###############################################################
#  Generated by:      Cadence Innovus 21.16-s078_1
#  OS:                Linux x86_64(Host ID tc-01a0e839f97e)
#  Generated on:      Wed Nov  4 16:08:58 2026
#  Design:            my_soc_top
#  Command:           write_lef_abstract -5.8 -cutObsMinSpacing -specifyTopLayer METAL6 ../my_soc_top/outputs/manual_final/my_soc_top.lef
###############################################################

VERSION 5.8 ;

BUSBITCHARS "[]" ;
DIVIDERCHAR "/" ;

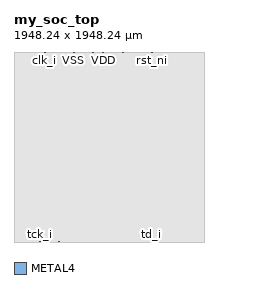
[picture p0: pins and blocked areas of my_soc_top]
MACRO my_soc_top
  CLASS BLOCK ;
  SIZE 1948.240000 BY 1948.240000 ;
  FOREIGN my_soc_top 0.000000 0.000000 ;
  ORIGIN 0 0 ;
  SYMMETRY X Y R90 ;
  PIN clk_i
    DIRECTION INPUT ;
    USE SIGNAL ;
    ANTENNADIFFAREA 1919.04 LAYER METAL4  ;
    ANTENNAPARTIALMETALAREA 298 LAYER METAL4  ;
    ANTENNAPARTIALMETALSIDEAREA 116.812 LAYER METAL4  ;
    ANTENNAMODEL OXIDE1 ;
    ANTENNAGATEAREA 7.5 LAYER METAL4  ;
    ANTENNAMAXAREACAR 92.4967 LAYER METAL4  ;
    ANTENNAMAXSIDEAREACAR 157.132 LAYER METAL4  ;
    ANTENNAMAXCUTCAR 15.6832 LAYER VIA45  ;
    PORT
      LAYER METAL4 ;
        RECT 310.000000 1945.840000 320.000000 1946.840000 ;
    END
  END clk_i
  PIN rst_ni
    DIRECTION INPUT ;
    USE SIGNAL ;
    ANTENNADIFFAREA 1919.04 LAYER METAL4  ;
    ANTENNAPARTIALMETALAREA 298 LAYER METAL4  ;
    ANTENNAPARTIALMETALSIDEAREA 116.812 LAYER METAL4  ;
    ANTENNAMODEL OXIDE1 ;
    ANTENNAGATEAREA 7.5 LAYER METAL4  ;
    ANTENNAMAXAREACAR 92.4967 LAYER METAL4  ;
    ANTENNAMAXSIDEAREACAR 157.132 LAYER METAL4  ;
    ANTENNAMAXCUTCAR 15.6832 LAYER VIA45  ;
    PORT
      LAYER METAL4 ;
        RECT 1410.000000 1945.840000 1420.000000 1946.840000 ;
    END
  END rst_ni
  PIN tck_i
    DIRECTION INPUT ;
    USE SIGNAL ;
    ANTENNADIFFAREA 1919.04 LAYER METAL4  ;
    ANTENNAPARTIALMETALAREA 298 LAYER METAL4  ;
    ANTENNAPARTIALMETALSIDEAREA 116.812 LAYER METAL4  ;
    ANTENNAMODEL OXIDE1 ;
    ANTENNAGATEAREA 7.5 LAYER METAL4  ;
    ANTENNAMAXAREACAR 92.4967 LAYER METAL4  ;
    ANTENNAMAXSIDEAREACAR 157.132 LAYER METAL4  ;
    ANTENNAMAXCUTCAR 15.6832 LAYER VIA45  ;
    PORT
      LAYER METAL4 ;
        RECT 260.000000 1.000000 270.000000 2.000000 ;
    END
  END tck_i
  PIN tms_i
    DIRECTION INPUT ;
    USE SIGNAL ;
    ANTENNADIFFAREA 1919.04 LAYER METAL4  ;
    ANTENNAPARTIALMETALAREA 298 LAYER METAL4  ;
    ANTENNAPARTIALMETALSIDEAREA 116.812 LAYER METAL4  ;
    ANTENNAMODEL OXIDE1 ;
    ANTENNAGATEAREA 7.5 LAYER METAL4  ;
    ANTENNAMAXAREACAR 92.4967 LAYER METAL4  ;
    ANTENNAMAXSIDEAREACAR 157.132 LAYER METAL4  ;
    ANTENNAMAXCUTCAR 15.6832 LAYER VIA45  ;
    PORT
      LAYER METAL4 ;
        RECT 460.000000 1.000000 470.000000 2.000000 ;
    END
  END tms_i
  PIN td_i
    DIRECTION INPUT ;
    USE SIGNAL ;
    ANTENNADIFFAREA 1919.04 LAYER METAL4  ;
    ANTENNAPARTIALMETALAREA 298 LAYER METAL4  ;
    ANTENNAPARTIALMETALSIDEAREA 116.812 LAYER METAL4  ;
    ANTENNAMODEL OXIDE1 ;
    ANTENNAGATEAREA 7.5 LAYER METAL4  ;
    ANTENNAMAXAREACAR 92.4967 LAYER METAL4  ;
    ANTENNAMAXSIDEAREACAR 157.132 LAYER METAL4  ;
    ANTENNAMAXCUTCAR 15.6832 LAYER VIA45  ;
    PORT
      LAYER METAL4 ;
        RECT 1410.000000 1.000000 1420.000000 2.000000 ;
    END
  END td_i
  PIN td_o
    DIRECTION OUTPUT ;
    USE SIGNAL ;
    ANTENNADIFFAREA 1919.04 LAYER METAL4  ;
    ANTENNAPARTIALMETALAREA 298 LAYER METAL4  ;
    ANTENNAPARTIALMETALSIDEAREA 116.812 LAYER METAL4  ;
    ANTENNAMODEL OXIDE1 ;
    ANTENNAGATEAREA 7.5 LAYER METAL4  ;
    ANTENNAMAXAREACAR 92.4967 LAYER METAL4  ;
    ANTENNAMAXSIDEAREACAR 157.132 LAYER METAL4  ;
    ANTENNAMAXCUTCAR 15.6832 LAYER VIA45  ;
    PORT
      LAYER METAL4 ;
        RECT 1610.000000 1.000000 1620.000000 2.000000 ;
    END
  END td_o
  PIN VDD
    DIRECTION INOUT ;
    USE POWER ;
    PORT
      LAYER METAL4 ;
        RECT 910.000000 1945.840000 920.000000 1946.840000 ;
    END
  END VDD
  PIN VSS
    DIRECTION INOUT ;
    USE GROUND ;
    PORT
      LAYER METAL4 ;
        RECT 610.000000 1945.840000 620.000000 1946.840000 ;
    END
  END VSS
  PIN VDDPST
    DIRECTION INOUT ;
    USE POWER ;
    PORT
      LAYER METAL4 ;
        RECT 1110.000000 1945.840000 1120.000000 1946.840000 ;
    END
  END VDDPST
  PIN VSSPST
    DIRECTION INOUT ;
    USE GROUND ;
    PORT
      LAYER METAL4 ;
        RECT 810.000000 1945.840000 820.000000 1946.840000 ;
    END
  END VSSPST
  OBS
    LAYER METAL1 ;
      RECT 0.000000 0.000000 1948.240000 1948.240000 ;
    LAYER METAL2 ;
      RECT 0.000000 0.000000 1948.240000 1948.240000 ;
    LAYER METAL3 ;
      RECT 0.000000 0.000000 1948.240000 1948.240000 ;
    LAYER METAL4 ;
      RECT 0.000000 1947.120000 1948.240000 1948.240000 ;
      RECT 1420.280000 1945.560000 1948.240000 1947.120000 ;
      RECT 1120.280000 1945.560000 1409.720000 1947.120000 ;
      RECT 920.280000 1945.560000 1109.720000 1947.120000 ;
      RECT 820.280000 1945.560000 909.720000 1947.120000 ;
      RECT 620.280000 1945.560000 809.720000 1947.120000 ;
      RECT 320.280000 1945.560000 609.720000 1947.120000 ;
      RECT 0.000000 1945.560000 309.720000 1947.120000 ;
      RECT 0.000000 2.280000 1948.240000 1945.560000 ;
      RECT 1620.280000 0.720000 1948.240000 2.280000 ;
      RECT 1420.280000 0.720000 1609.720000 2.280000 ;
      RECT 470.280000 0.720000 1409.720000 2.280000 ;
      RECT 270.280000 0.720000 459.720000 2.280000 ;
      RECT 0.000000 0.720000 259.720000 2.280000 ;
      RECT 0.000000 0.000000 1948.240000 0.720000 ;
    LAYER METAL5 ;
      RECT 0.000000 0.000000 1948.240000 1948.240000 ;
    LAYER METAL6 ;
      RECT 0.000000 0.000000 1948.240000 1948.240000 ;
  END
END my_soc_top

END LIBRARY
